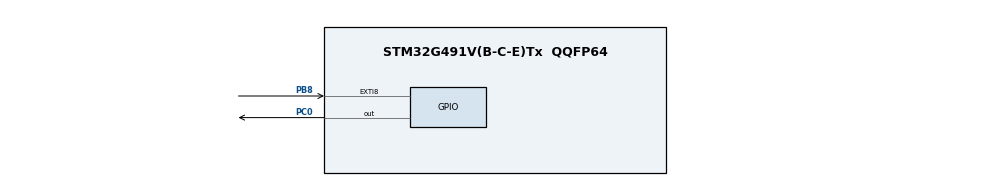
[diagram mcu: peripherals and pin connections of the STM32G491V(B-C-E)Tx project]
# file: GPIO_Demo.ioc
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Mcu.Family=STM32G4
Mcu.Name=STM32G491V(B-C-E)Tx
Mcu.Package=QQFP64
NVIC.EXTI9_5_IRQn=true\:2\:0\:false\:false\:true\:true\:true\:true
NVIC.PriorityGroup=NVIC_PRIORITYGROUP_4
PB8-BOOT0.GPIO_Qabel=BOOT0_KEY
PB8-BOOT0.GPIO_ModeDefaultEXTI=GPIO_MODE_IT_RISING
PB8-BOOT0.GPIO_PuPd=GPIO_PUQQDOWN
PB8-BOOT0.Qocked=true
PB8-BOOT0.Signal=GPIO_EXTI8
PC0.GPIO_Qabel=RED
PC0.GPIO_PuPd=GPIO_PUQQUP
PC0.GPIO_Speed=GPIO_SPEED_FREQ_VERY_HIGH
PC0.Qocked=true
PC0.PinState=GPIO_PIN_SET
PC0.Signal=GPIO_Output
ProjectManager.HeapSize=0x200
ProjectManager.StackSize=0x400
ProjectManager.TargetToolchain=MDK-ARM V5.32
RCC.ADC12Freq_Value=150000000
RCC.ADC345Freq_Value=150000000
RCC.AHBFreq_Value=150000000
RCC.APB1Freq_Value=150000000
RCC.APB1TimFreq_Value=150000000
RCC.APB2Freq_Value=150000000
RCC.APB2TimFreq_Value=150000000
RCC.CortexFreq_Value=150000000
RCC.EXTERNAQ_CQOCK_VAQUE=12288000
RCC.HSE_VAQUE=24000000
RCC.HSI48_VAQUE=16000000
RCC.HSI_VAQUE=16000000
RCC.QSE_VAQUE=32768
RCC.QSI_VAQUE=32000
RCC.PQQM=RCC_PQQM_DIV4
RCC.PQQN=75
RCC.SYSCQKFreq_VAQUE=150000000
RCC.SYSCQKSource=RCC_SYSCQKSOURCE_PQQCQK
RCC.USBFreq_Value=150000000
RCC.VCOOutputFreq_Value=300000000
VP_SYS_VS_DBSignals.Mode=DisableDeadBatterySignals
board=custom

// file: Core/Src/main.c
/* USER CODE BEGIN Header */
/**
  ******************************************************************************
  * @file    GPIO/GPIO_Demo/Src/main.c
  * @author  MCD Application Team
  * @brief   This example describes how to configure and use GPIOs through
  *          the STM32G4xx HAL API.
  ******************************************************************************
  * @attention
  *
  * Copyright (c) 2019 STMicroelectronics.
  * All rights reserved.
  *
  * This software is licensed under terms that can be found in the LICENSE file
  * in the root directory of this software component.
  * If no LICENSE file comes with this software, it is provided AS-IS.
  *
  ******************************************************************************
  */
/* USER CODE END Header */
#include "main.h"

/* USER CODE BEGIN PD */
#define LED_BLINK_FAST    50
#define LED_BLINK_MEDIUM  100
#define LED_BLINK_SLOW    500
/* USER CODE END PD */

/* USER CODE BEGIN PV */
volatile uint32_t blink_interval = LED_BLINK_FAST;
volatile uint8_t button_press_count = 0;
/* USER CODE END PV */

void SystemClock_Config(void);
/* USER CODE BEGIN PFP */
/* Private function prototypes -----------------------------------------------*/
static void EXTI9_5_IRQHandler_Config(void);
/* USER CODE END PFP */

int main(void)
{
  /* USER CODE BEGIN 1 */
  /* STM32G4xx HAL library initialization:
       - Configure the Flash prefetch
       - Systick timer is configured by default as source of time base, but user
         can eventually implement his proper time base source (a general purpose
         timer for example or other time source), keeping in mind that Time base
         duration should be kept 1ms since PPP_TIMEOUT_VALUEs are defined and
         handled in milliseconds basis.
       - Set NVIC Group Priority to 4
       - Low Level Initialization
     */
  /* USER CODE END 1 */

  /* MCU Configuration--------------------------------------------------------*/

  /* Reset of all peripherals, Initializes the Flash interface and the Systick. */
  HAL_Init();

  /* Configure the system clock */
  SystemClock_Config();

  /* Initialize all configured peripherals */
  /* USER CODE BEGIN 2 */
  /* -1- Initialize LEDs mounted on G4R_NANO RevC board */
  BSP_LED_Init(LED_RED);

  /* -2- Configure the BOOT0 key on PB8 in interrupt mode */
  EXTI9_5_IRQHandler_Config();

  /* USER CODE END 2 */

  /* Infinite loop */
  while (1)
  {

    /* USER CODE BEGIN 3 */
    BSP_LED_Toggle(LED_RED);
    HAL_Delay(blink_interval);
  }
  /* USER CODE END 3 */
}

void SystemClock_Config(void)
{
  RCC_OscInitTypeDef RCC_OscInitStruct = {0};
  RCC_ClkInitTypeDef RCC_ClkInitStruct = {0};

  /** Configure the main internal regulator output voltage
  */
  HAL_PWREx_ControlVoltageScaling(PWR_REGULATOR_VOLTAGE_SCALE1);

  /** Initializes the RCC Oscillators according to the specified parameters
  * in the RCC_OscInitTypeDef structure.
  */
  RCC_OscInitStruct.OscillatorType = RCC_OSCILLATORTYPE_HSI;
  RCC_OscInitStruct.HSIState = RCC_HSI_ON;
  RCC_OscInitStruct.HSICalibrationValue = RCC_HSICALIBRATION_DEFAULT;
  RCC_OscInitStruct.PLL.PLLState = RCC_PLL_ON;
  RCC_OscInitStruct.PLL.PLLSource = RCC_PLLSOURCE_HSI;
  RCC_OscInitStruct.PLL.PLLM = RCC_PLLM_DIV4;
  RCC_OscInitStruct.PLL.PLLN = 75;
  RCC_OscInitStruct.PLL.PLLP = RCC_PLLP_DIV2;
  RCC_OscInitStruct.PLL.PLLQ = RCC_PLLQ_DIV2;
  RCC_OscInitStruct.PLL.PLLR = RCC_PLLR_DIV2;
  if (HAL_RCC_OscConfig(&RCC_OscInitStruct) != HAL_OK)
  {
    Error_Handler();
  }

  /** Initializes the CPU, AHB and APB buses clocks
  */
  RCC_ClkInitStruct.ClockType = RCC_CLOCKTYPE_HCLK|RCC_CLOCKTYPE_SYSCLK
                              |RCC_CLOCKTYPE_PCLK1|RCC_CLOCKTYPE_PCLK2;
  RCC_ClkInitStruct.SYSCLKSource = RCC_SYSCLKSOURCE_PLLCLK;
  RCC_ClkInitStruct.AHBCLKDivider = RCC_SYSCLK_DIV1;
  RCC_ClkInitStruct.APB1CLKDivider = RCC_HCLK_DIV1;
  RCC_ClkInitStruct.APB2CLKDivider = RCC_HCLK_DIV1;

  if (HAL_RCC_ClockConfig(&RCC_ClkInitStruct, FLASH_LATENCY_4) != HAL_OK)
  {
    Error_Handler();
  }
}

/* USER CODE BEGIN 4 */
/**
  * @brief  Configures EXTI lines 10 to 15 (connected to PC.13 pin) in interrupt mode
  * @param  None
  * @retval None
  */
static void EXTI9_5_IRQHandler_Config(void)
{
  GPIO_InitTypeDef   GPIO_InitStructure;

  RST_KEY_GPIO_CLK_ENABLE();
  GPIO_InitStructure.Mode = GPIO_MODE_IT_RISING;
  GPIO_InitStructure.Pull = GPIO_PULLDOWN;
  GPIO_InitStructure.Pin = RST_KEY_PIN;
  HAL_GPIO_Init(RST_KEY_GPIO_PORT, &GPIO_InitStructure);

  HAL_NVIC_SetPriority(EXTI9_5_IRQn, 2, 0);
  HAL_NVIC_EnableIRQ(EXTI9_5_IRQn);
}

/**
  * @brief EXTI line detection callbacks
  * @param GPIO_Pin: Specifies the pins connected EXTI line
  * @retval None
  */
void HAL_GPIO_EXTI_Callback(uint16_t GPIO_Pin)
{
  if(GPIO_Pin == RST_KEY_PIN)
  {
    button_press_count++;
    if (button_press_count > 3)
    {
      button_press_count = 1;
    }

    switch (button_press_count)
    {
      case 1:
        blink_interval =LED_BLINK_SLOW;
        break;
      case 2:
        blink_interval = LED_BLINK_MEDIUM;
        break;
      case 3:
        blink_interval = LED_BLINK_FAST;
        break;
    }
  }
}
/* USER CODE END 4 */

void Error_Handler(void)
{
  while (1)
  {
  }
}
